One B-rep face of a CAD part: STEP entity #1316.
In plain terms, the planar face has unit normal (1, 0, 0).
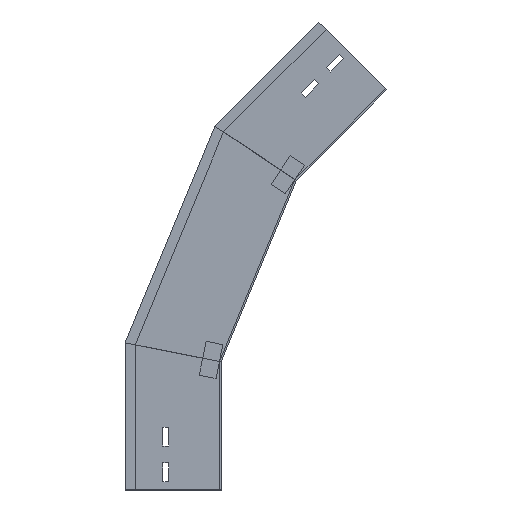
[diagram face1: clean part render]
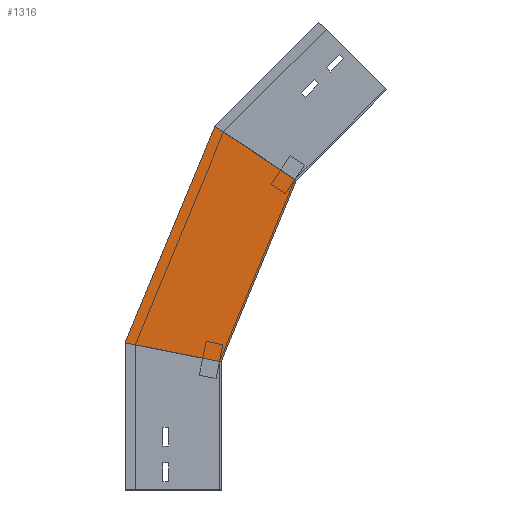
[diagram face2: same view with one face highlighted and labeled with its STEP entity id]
Its self-contained STEP definition (entity closure, numbers rounded to 3 decimals):
#27 = VECTOR ( 'NONE', #1132, 1000. ) ;
#260 = ORIENTED_EDGE ( 'NONE', *, *, #262, .F. ) ;
#262 = EDGE_CURVE ( 'NONE', #544, #1107, #874, .T. ) ;
#324 = EDGE_CURVE ( 'NONE', #799, #544, #704, .T. ) ;
#374 = CARTESIAN_POINT ( 'NONE',  ( 0., 9.458, 127.166 ) ) ;
#398 = ORIENTED_EDGE ( 'NONE', *, *, #1141, .T. ) ;
#402 = DIRECTION ( 'NONE',  ( 0., 0., -1. ) ) ;
#407 = LINE ( 'NONE', #432, #27 ) ;
#416 = ORIENTED_EDGE ( 'NONE', *, *, #324, .F. ) ;
#432 = CARTESIAN_POINT ( 'NONE',  ( 0., 113.395, 170.218 ) ) ;
#443 = CARTESIAN_POINT ( 'NONE',  ( 0., -129.335, 334.885 ) ) ;
#528 = DIRECTION ( 'NONE',  ( 1., 0., 0. ) ) ;
#544 = VERTEX_POINT ( 'NONE', #1338 ) ;
#573 = CARTESIAN_POINT ( 'NONE',  ( 0., 112.5, 172.378 ) ) ;
#651 = PLANE ( 'NONE',  #1088 ) ;
#664 = EDGE_CURVE ( 'NONE', #799, #929, #407, .T. ) ;
#704 = LINE ( 'NONE', #1043, #1297 ) ;
#707 = LINE ( 'NONE', #443, #813 ) ;
#753 = CARTESIAN_POINT ( 'NONE',  ( 0., 9.458, 127.166 ) ) ;
#773 = FACE_OUTER_BOUND ( 'NONE', #1350, .T. ) ;
#799 = VERTEX_POINT ( 'NONE', #573 ) ;
#813 = VECTOR ( 'NONE', #908, 1000. ) ;
#874 = LINE ( 'NONE', #374, #1171 ) ;
#908 = DIRECTION ( 'NONE',  ( 0., -0.831, -0.556 ) ) ;
#929 = VERTEX_POINT ( 'NONE', #1090 ) ;
#1043 = CARTESIAN_POINT ( 'NONE',  ( 0., -28.701, 144.291 ) ) ;
#1088 = AXIS2_PLACEMENT_3D ( 'NONE', #753, #528, #402 ) ;
#1090 = CARTESIAN_POINT ( 'NONE',  ( 0., 7.356, 426.218 ) ) ;
#1107 = VERTEX_POINT ( 'NONE', #1283 ) ;
#1132 = DIRECTION ( 'NONE',  ( 0., -0.383, 0.924 ) ) ;
#1141 = EDGE_CURVE ( 'NONE', #929, #1107, #707, .T. ) ;
#1159 = DIRECTION ( 'NONE',  ( 0., -0.981, -0.195 ) ) ;
#1171 = VECTOR ( 'NONE', #1182, 1000. ) ;
#1182 = DIRECTION ( 'NONE',  ( 0., -0.383, 0.924 ) ) ;
#1283 = CARTESIAN_POINT ( 'NONE',  ( 0., -88.017, 362.492 ) ) ;
#1297 = VECTOR ( 'NONE', #1159, 1000. ) ;
#1316 = ADVANCED_FACE ( 'NONE', ( #773 ), #651, .T. ) ;
#1338 = CARTESIAN_POINT ( 'NONE',  ( 0., 0., 150. ) ) ;
#1350 = EDGE_LOOP ( 'NONE', ( #1402, #398, #260, #416 ) ) ;
#1402 = ORIENTED_EDGE ( 'NONE', *, *, #664, .T. ) ;
